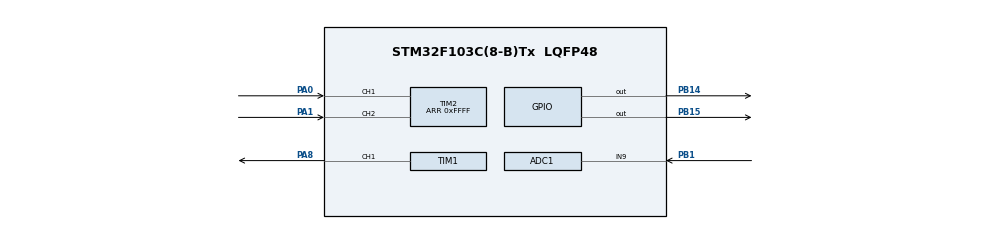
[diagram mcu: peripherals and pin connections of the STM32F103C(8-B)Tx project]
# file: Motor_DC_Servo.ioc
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ADC1.Channel-0\#ChannelRegularConversion=ADC_CHANNEL_9
ADC1.ContinuousConvMode=ENABLE
ADC1.NbrOfConversionFlag=1
ADC1.Rank-0\#ChannelRegularConversion=1
ADC1.SamplingTime-0\#ChannelRegularConversion=ADC_SAMPLETIME_1CYCLE_5
ADC1.master=1
Mcu.Family=STM32F1
Mcu.Name=STM32F103C(8-B)Tx
Mcu.Package=LQFP48
NVIC.PriorityGroup=NVIC_PRIORITYGROUP_4
PA0-WKUP.GPIO_PuPd=GPIO_PULLUP
PA0-WKUP.Signal=S_TIM2_CH1_ETR
PA1.GPIO_PuPd=GPIO_PULLUP
PA1.Signal=S_TIM2_CH2
PA13.Mode=Serial_Wire
PA13.Signal=SYS_JTMS-SWDIO
PA14.Mode=Serial_Wire
PA14.Signal=SYS_JTCK-SWCLK
PA8.GPIO_Speed=GPIO_SPEED_FREQ_MEDIUM
PA8.Signal=S_TIM1_CH1
PB1.Signal=ADCx_IN9
PB14.Signal=GPIO_Output
PB15.Signal=GPIO_Output
PD0-OSC_IN.Mode=HSE-External-Oscillator
PD0-OSC_IN.Signal=RCC_OSC_IN
PD1-OSC_OUT.Mode=HSE-External-Oscillator
PD1-OSC_OUT.Signal=RCC_OSC_OUT
ProjectManager.HeapSize=0x200
ProjectManager.StackSize=0x400
ProjectManager.TargetToolchain=MDK-ARM V5
RCC.APB1Freq_Value=8000000
RCC.APB2Freq_Value=8000000
RCC.SYSCLKSource=RCC_SYSCLKSOURCE_HSE
SH.ADCx_IN9.0=ADC1_IN9,IN9
SH.S_TIM1_CH1.0=TIM1_CH1,PWM Generation1 CH1
SH.S_TIM2_CH1_ETR.0=TIM2_CH1,Encoder_Interface
SH.S_TIM2_CH2.0=TIM2_CH2,Encoder_Interface
TIM1.Channel-PWM\ Generation1\ CH1=TIM_CHANNEL_1
TIM1.Period=999
TIM1.Prescaler=0
TIM1.Pulse-PWM\ Generation1\ CH1=499
TIM2.EncoderMode=TIM_ENCODERMODE_TI12
TIM2.Period=0xFFFF
VP_TIM1_VS_ClockSourceINT.Mode=Internal
board=custom

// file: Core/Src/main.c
/* USER CODE BEGIN Header */
/**
  ******************************************************************************
  * @file           : main.c
  * @brief          : Main program body
  ******************************************************************************
  * @attention
  *
  * <h2><center>&copy; Copyright (c) 2023 STMicroelectronics.
  * All rights reserved.</center></h2>
  *
  * This software component is licensed by ST under BSD 3-Clause license,
  * the "License"; You may not use this file except in compliance with the
  * License. You may obtain a copy of the License at:
  *                        opensource.org/licenses/BSD-3-Clause
  *
  ******************************************************************************
  */
/* USER CODE END Header */
#include "main.h"

/* USER CODE BEGIN Includes */
	int16_t xung1=0;
	//int16_t xung2=0;
	float rate1=0;
	//float rate2=0;
/* USER CODE END Includes */

ADC_HandleTypeDef hadc1;

TIM_HandleTypeDef htim1;
TIM_HandleTypeDef htim2;

void SystemClock_Config(void);
static void MX_GPIO_Init(void);
static void MX_TIM1_Init(void);
static void MX_TIM2_Init(void);
static void MX_ADC1_Init(void);

int main(void)
{

  /* MCU Configuration--------------------------------------------------------*/

  /* Reset of all peripherals, Initializes the Flash interface and the Systick. */
  HAL_Init();

  /* Configure the system clock */
  SystemClock_Config();

  /* Initialize all configured peripherals */
  MX_GPIO_Init();
  MX_TIM1_Init();
  MX_TIM2_Init();
  MX_ADC1_Init();
  /* USER CODE BEGIN 2 */
	HAL_TIM_PWM_Start(&htim1, TIM_CHANNEL_1);

  HAL_TIM_Encoder_Start(&htim2, TIM_CHANNEL_1);
  HAL_TIM_Encoder_Start(&htim2, TIM_CHANNEL_2);

  /* USER CODE END 2 */

  /* Infinite loop */
  while (1)
  {

    /* USER CODE BEGIN 3 */
		__HAL_TIM_SetCompare (&htim1,TIM_CHANNEL_1,250);
	  HAL_GPIO_WritePin(GPIOA, GPIO_PIN_14, 0);
	  HAL_GPIO_WritePin(GPIOA, GPIO_PIN_15, 1);

	  xung1 = __HAL_TIM_GET_COUNTER(&htim2);
	  rate1 = (float)xung1/234.3/2*60 ;
	  TIM2->CNT = 0;
	  TIM3->CNT = 0;
	  HAL_Delay(1000);
  }
  /* USER CODE END 3 */
}

void SystemClock_Config(void)
{
  RCC_OscInitTypeDef RCC_OscInitStruct = {0};
  RCC_ClkInitTypeDef RCC_ClkInitStruct = {0};
  RCC_PeriphCLKInitTypeDef PeriphClkInit = {0};

  /** Initializes the RCC Oscillators according to the specified parameters
  * in the RCC_OscInitTypeDef structure.
  */
  RCC_OscInitStruct.OscillatorType = RCC_OSCILLATORTYPE_HSE;
  RCC_OscInitStruct.HSEState = RCC_HSE_ON;
  RCC_OscInitStruct.PLL.PLLState = RCC_PLL_NONE;
  if (HAL_RCC_OscConfig(&RCC_OscInitStruct) != HAL_OK)
  {
    Error_Handler();
  }
  /** Initializes the CPU, AHB and APB buses clocks
  */
  RCC_ClkInitStruct.ClockType = RCC_CLOCKTYPE_HCLK|RCC_CLOCKTYPE_SYSCLK
                              |RCC_CLOCKTYPE_PCLK1|RCC_CLOCKTYPE_PCLK2;
  RCC_ClkInitStruct.SYSCLKSource = RCC_SYSCLKSOURCE_HSE;
  RCC_ClkInitStruct.AHBCLKDivider = RCC_SYSCLK_DIV1;
  RCC_ClkInitStruct.APB1CLKDivider = RCC_HCLK_DIV1;
  RCC_ClkInitStruct.APB2CLKDivider = RCC_HCLK_DIV1;

  if (HAL_RCC_ClockConfig(&RCC_ClkInitStruct, FLASH_LATENCY_0) != HAL_OK)
  {
    Error_Handler();
  }
  PeriphClkInit.PeriphClockSelection = RCC_PERIPHCLK_ADC;
  PeriphClkInit.AdcClockSelection = RCC_ADCPCLK2_DIV2;
  if (HAL_RCCEx_PeriphCLKConfig(&PeriphClkInit) != HAL_OK)
  {
    Error_Handler();
  }
}

static void MX_ADC1_Init(void)
{

  ADC_ChannelConfTypeDef sConfig = {0};

  /** Common config
  */
  hadc1.Instance = ADC1;
  hadc1.Init.ScanConvMode = ADC_SCAN_DISABLE;
  hadc1.Init.ContinuousConvMode = ENABLE;
  hadc1.Init.DiscontinuousConvMode = DISABLE;
  hadc1.Init.ExternalTrigConv = ADC_SOFTWARE_START;
  hadc1.Init.DataAlign = ADC_DATAALIGN_RIGHT;
  hadc1.Init.NbrOfConversion = 1;
  if (HAL_ADC_Init(&hadc1) != HAL_OK)
  {
    Error_Handler();
  }
  /** Configure Regular Channel
  */
  sConfig.Channel = ADC_CHANNEL_9;
  sConfig.Rank = ADC_REGULAR_RANK_1;
  sConfig.SamplingTime = ADC_SAMPLETIME_1CYCLE_5;
  if (HAL_ADC_ConfigChannel(&hadc1, &sConfig) != HAL_OK)
  {
    Error_Handler();
  }

}

static void MX_TIM1_Init(void)
{

  TIM_ClockConfigTypeDef sClockSourceConfig = {0};
  TIM_MasterConfigTypeDef sMasterConfig = {0};
  TIM_OC_InitTypeDef sConfigOC = {0};
  TIM_BreakDeadTimeConfigTypeDef sBreakDeadTimeConfig = {0};

  htim1.Instance = TIM1;
  htim1.Init.Prescaler = 0;
  htim1.Init.CounterMode = TIM_COUNTERMODE_UP;
  htim1.Init.Period = 999;
  htim1.Init.ClockDivision = TIM_CLOCKDIVISION_DIV1;
  htim1.Init.RepetitionCounter = 0;
  htim1.Init.AutoReloadPreload = TIM_AUTORELOAD_PRELOAD_DISABLE;
  if (HAL_TIM_Base_Init(&htim1) != HAL_OK)
  {
    Error_Handler();
  }
  sClockSourceConfig.ClockSource = TIM_CLOCKSOURCE_INTERNAL;
  if (HAL_TIM_ConfigClockSource(&htim1, &sClockSourceConfig) != HAL_OK)
  {
    Error_Handler();
  }
  if (HAL_TIM_PWM_Init(&htim1) != HAL_OK)
  {
    Error_Handler();
  }
  sMasterConfig.MasterOutputTrigger = TIM_TRGO_RESET;
  sMasterConfig.MasterSlaveMode = TIM_MASTERSLAVEMODE_DISABLE;
  if (HAL_TIMEx_MasterConfigSynchronization(&htim1, &sMasterConfig) != HAL_OK)
  {
    Error_Handler();
  }
  sConfigOC.OCMode = TIM_OCMODE_PWM1;
  sConfigOC.Pulse = 499;
  sConfigOC.OCPolarity = TIM_OCPOLARITY_HIGH;
  sConfigOC.OCNPolarity = TIM_OCNPOLARITY_HIGH;
  sConfigOC.OCFastMode = TIM_OCFAST_DISABLE;
  sConfigOC.OCIdleState = TIM_OCIDLESTATE_RESET;
  sConfigOC.OCNIdleState = TIM_OCNIDLESTATE_RESET;
  if (HAL_TIM_PWM_ConfigChannel(&htim1, &sConfigOC, TIM_CHANNEL_1) != HAL_OK)
  {
    Error_Handler();
  }
  sBreakDeadTimeConfig.OffStateRunMode = TIM_OSSR_DISABLE;
  sBreakDeadTimeConfig.OffStateIDLEMode = TIM_OSSI_DISABLE;
  sBreakDeadTimeConfig.LockLevel = TIM_LOCKLEVEL_OFF;
  sBreakDeadTimeConfig.DeadTime = 0;
  sBreakDeadTimeConfig.BreakState = TIM_BREAK_DISABLE;
  sBreakDeadTimeConfig.BreakPolarity = TIM_BREAKPOLARITY_HIGH;
  sBreakDeadTimeConfig.AutomaticOutput = TIM_AUTOMATICOUTPUT_DISABLE;
  if (HAL_TIMEx_ConfigBreakDeadTime(&htim1, &sBreakDeadTimeConfig) != HAL_OK)
  {
    Error_Handler();
  }
  HAL_TIM_MspPostInit(&htim1);

}

static void MX_TIM2_Init(void)
{

  TIM_Encoder_InitTypeDef sConfig = {0};
  TIM_MasterConfigTypeDef sMasterConfig = {0};

  htim2.Instance = TIM2;
  htim2.Init.Prescaler = 0;
  htim2.Init.CounterMode = TIM_COUNTERMODE_UP;
  htim2.Init.Period = 0xFFFF;
  htim2.Init.ClockDivision = TIM_CLOCKDIVISION_DIV1;
  htim2.Init.AutoReloadPreload = TIM_AUTORELOAD_PRELOAD_DISABLE;
  sConfig.EncoderMode = TIM_ENCODERMODE_TI12;
  sConfig.IC1Polarity = TIM_ICPOLARITY_RISING;
  sConfig.IC1Selection = TIM_ICSELECTION_DIRECTTI;
  sConfig.IC1Prescaler = TIM_ICPSC_DIV1;
  sConfig.IC1Filter = 0;
  sConfig.IC2Polarity = TIM_ICPOLARITY_RISING;
  sConfig.IC2Selection = TIM_ICSELECTION_DIRECTTI;
  sConfig.IC2Prescaler = TIM_ICPSC_DIV1;
  sConfig.IC2Filter = 0;
  if (HAL_TIM_Encoder_Init(&htim2, &sConfig) != HAL_OK)
  {
    Error_Handler();
  }
  sMasterConfig.MasterOutputTrigger = TIM_TRGO_RESET;
  sMasterConfig.MasterSlaveMode = TIM_MASTERSLAVEMODE_DISABLE;
  if (HAL_TIMEx_MasterConfigSynchronization(&htim2, &sMasterConfig) != HAL_OK)
  {
    Error_Handler();
  }

}

static void MX_GPIO_Init(void)
{
  GPIO_InitTypeDef GPIO_InitStruct = {0};

  /* GPIO Ports Clock Enable */
  __HAL_RCC_GPIOD_CLK_ENABLE();
  __HAL_RCC_GPIOA_CLK_ENABLE();
  __HAL_RCC_GPIOB_CLK_ENABLE();

  /*Configure GPIO pin Output Level */
  HAL_GPIO_WritePin(GPIOA, GPIO_PIN_5, GPIO_PIN_RESET);

  /*Configure GPIO pin Output Level */
  HAL_GPIO_WritePin(GPIOA, GPIO_PIN_6, GPIO_PIN_SET);

  /*Configure GPIO pins : PA5 PA6 */
  GPIO_InitStruct.Pin = GPIO_PIN_5|GPIO_PIN_6;
  GPIO_InitStruct.Mode = GPIO_MODE_OUTPUT_PP;
  GPIO_InitStruct.Pull = GPIO_NOPULL;
  GPIO_InitStruct.Speed = GPIO_SPEED_FREQ_LOW;
  HAL_GPIO_Init(GPIOA, &GPIO_InitStruct);

}

void Error_Handler(void)
{
}

/************************ (C) COPYRIGHT STMicroelectronics *****END OF FILE****/
